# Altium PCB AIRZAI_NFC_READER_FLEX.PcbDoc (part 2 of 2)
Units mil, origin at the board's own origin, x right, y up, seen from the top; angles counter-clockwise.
Board outline 2897.24 x 5925.59 mil, 2 copper layers (Top Layer, Bottom Layer); 45 components, 43 nets, 193 pads, 92 vias.
Unrouted connection lines stored in the file: 129.

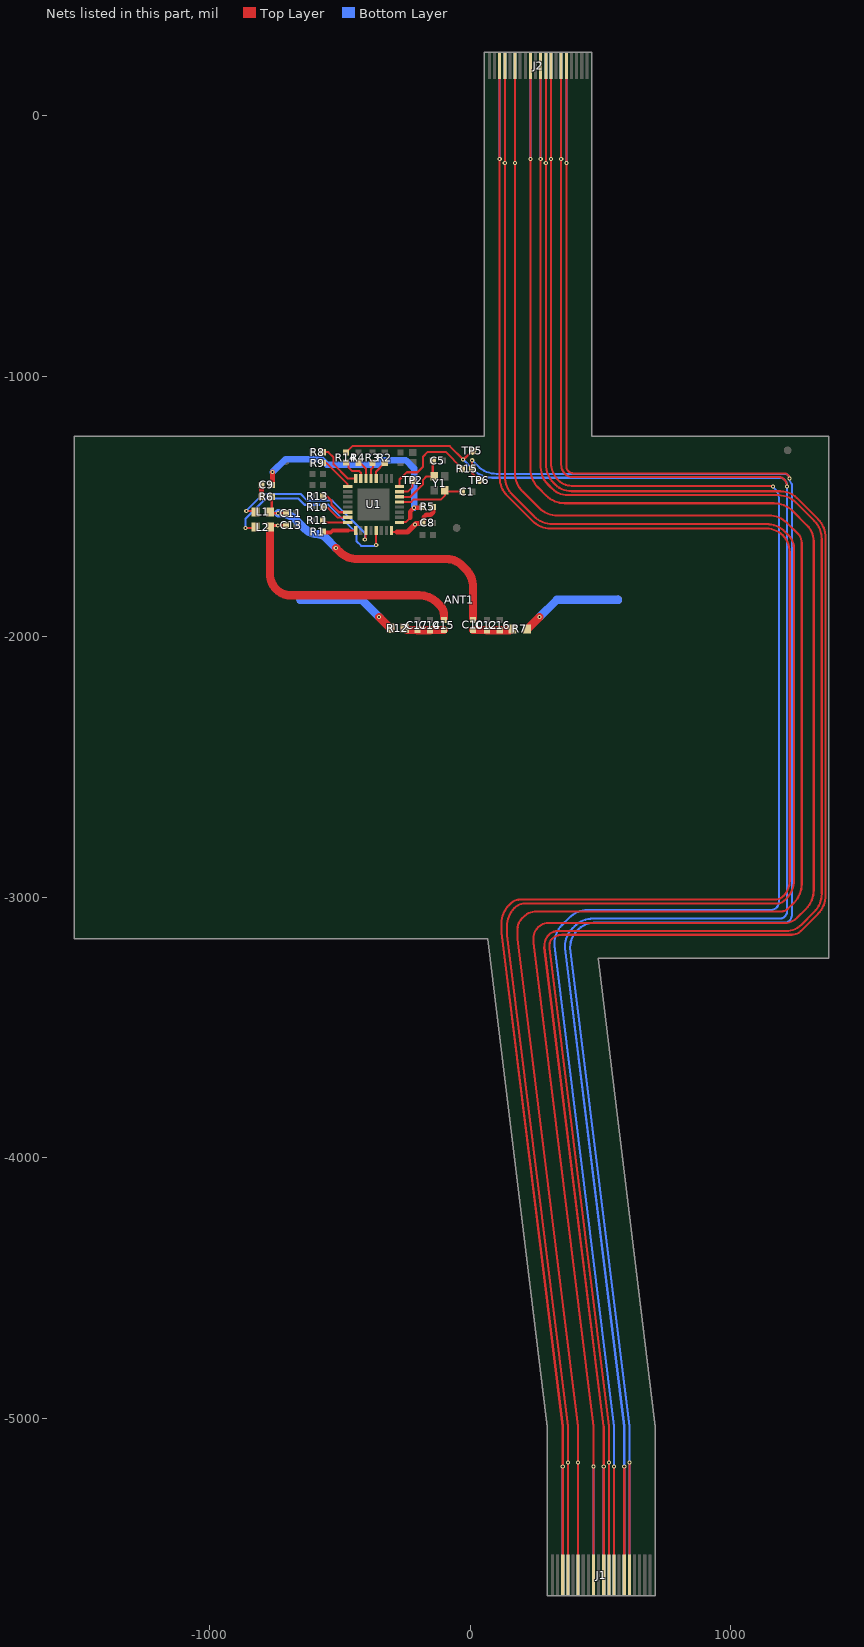
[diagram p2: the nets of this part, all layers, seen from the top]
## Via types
v1: diameter 16, hole 8, Top Layer to Bottom Layer, tented both sides, 81 vias
v2: diameter 19.68, hole 8, Top Layer to Bottom Layer, 9 vias
v3: diameter 30, hole 15, Top Layer to Bottom Layer, tented both sides, 2 vias

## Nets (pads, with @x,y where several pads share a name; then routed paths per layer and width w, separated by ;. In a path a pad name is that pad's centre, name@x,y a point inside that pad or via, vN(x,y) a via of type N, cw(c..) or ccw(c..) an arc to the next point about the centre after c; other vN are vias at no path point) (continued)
"LED Str DATA": J1.11 J2.11 | length 8505.9
  Top Layer w8: J2.11@270.72,192.91 270.72,-1348.01 ccw(c365.7,-1348.01) 298.54,-1415.17 308.25,-1424.88 ccw(c378.96,-1354.17) 315.47,-1431.43 ccw(c375.25,-1371.65) 375.25,-1456.19 1183.52,-1456.19 cw(c1183.52,-1549.31) 1249.37,-1483.46 1320.71,-1554.81 cw(c1250,-1625.52) 1350,-1625.52 1350,-2985.57 cw(c1250,-2985.57) 1320.71,-3056.28 1272,-3104.99 cw(c1211.64,-3044.64) 1211.64,-3129.99 335.8,-3129.99 ccw(c335.8,-3177.79) 302,-3143.99 ccw(c344.18,-3186.17) 284.53,-3186.17 284.53,-3190.73 ; 284.3,-3190.96 512.65,-5032.35 v1@512.65,-5186.17 ; J1.11@512.85,-5602.76 v1(512.85,-5186.17)
  Bottom Layer w8: v1@270.72,-164.99 J2.11@270.72,192.91 ; J1.11@512.85,-5602.76 v1(512.85,-5186.17)
  other v1: 270.72,-165.27
NetANT1_1: ANT1.1 R7.1 | length 396.1
  Top Layer w31.5: R7.1@217.78,-1969.52 ccw(c217.78,-1962.59) 222.68,-1967.49 v1(265.88,-1924.29)
  Bottom Layer w31.5: v1(265.88,-1924.29) 332.3,-1857.87 ; 332.3,-1857.85 ANT1.1@567.9,-1857.85
NetANT1_2: ANT1.2 R12.1 | length 391
  Top Layer w31.5: v1@-349.45,-1924.19 R12.1@-306.34,-1967.3
  Bottom Layer w31.5: ANT1.2@-652.1,-1857.85 -482.13,-1857.85 ; -482.13,-1857.87 -415.97,-1857.87 v1(-349.55,-1924.29)
NetC1_2: C1.2 U1.21 Y1.3 | length 268.4
  Top Layer w8: U1.21@-271.21,-1482.04 -225.83,-1482.04 -216.13,-1472.34 -111.34,-1472.34 -97.09,-1458.1 Y1.3@-97.09,-1437.14 -91.98,-1442.25 C1.2@-35.8,-1442.25
NetC5_2: C5.2 U1.22 Y1.1 | length 236.2
  Top Layer w8: U1.22@-271.21,-1462.36 -229.11,-1462.36 -181.8,-1415.05 -181.8,-1398.13 -167.8,-1384.13 -138.6,-1384.13 Y1.1@-138.46,-1383.99 -143.8,-1378.66 C5.2@-143.8,-1325.13
NetC9_1: C9.1 R6.2 | length 46.1
  Top Layer w20: R6.2@-801.38,-1462.43 -801.07,-1462.12 C9.1@-801.07,-1416.43
NetC9_2: C9.2 R5.2 U1.17 | length 919.8
  Top Layer w8: U1.17@-271.21,-1560.78 -269.11,-1558.68 -246.05,-1558.68 -230.8,-1543.43
  Top Layer w17: -230.8,-1543.43 -230.8,-1519.82 v1(-215.45,-1504.46) -186.26,-1504.46 R5.2@-182.95,-1501.15
  Top Layer w20: C9.2@-761.7,-1416.43 C9.2@-759.88,-1414.62 ; C9.2@-758.61,-1414.62 v1(-758.61,-1367.56)
  Bottom Layer w25: v1(-758.61,-1367.56) -708.66,-1317.6 -571.42,-1317.6 -550.14,-1338.88 -357.71,-1338.88 -341.17,-1322.35 -246.54,-1322.35 -215.45,-1353.44 v1(-215.45,-1504.46)
NetC10_1: C10.1 C12.2 C16.2 R7.2 | length 152.8
  Top Layer w31.5: C10.1@11.31,-1974.2 63.87,-1974.2 C12.2@64.22,-1974.55 C16.2@113.24,-1974.55 150.52,-1974.55 ccw(c150.52,-1957.38) R7.2@162.66,-1969.52
NetC10_2: C10.2 C11.2 L1.2 R6.1 | length 1115.1
  Top Layer w10: R6.1@-762.01,-1462.43 -762.01,-1513.62 L1.2@-768.82,-1520.43 -763.82,-1525.43 v1(-737.23,-1525.43) C11.2@-707.64,-1525.43 C11.2@-704.64,-1525.43
  Top Layer w31.5: v1@-515.38,-1658.99 -500.85,-1673.52 ccw(c-433.25,-1605.92) -433.25,-1701.52 -89.72,-1701.52 cw(c-89.72,-1783.46) -31.78,-1725.52 -17.98,-1739.32 cw(c-88.69,-1810.03) 11.31,-1810.03 11.31,-1896.52 C10.2@11.32,-1928.52
  Bottom Layer w31.5: v1(-737.23,-1525.43) -735.29,-1525.43 cw(c-735.29,-1625.43) -664.58,-1554.72 -632.16,-1587.13 ccw(c-587.78,-1542.75) -587.78,-1605.52 cw(c-587.78,-1651.22) -555.47,-1618.9 -516.31,-1658.06 -516.31,-1658.68 v1(-516,-1658.99)
NetC13_1: C13.1 C15.2 L2.2 | length 1011.1
  Top Layer w10: L2.2@-768.82,-1578.43 -762.82,-1572.43 v1(-738.6,-1572.43) C13.1@-707.63,-1572.43 C13.1@-704.63,-1572.43
  Top Layer w31.5: L2.2@-768.82,-1578.43 -768.82,-1758.02 ccw(c-683.32,-1758.02) -743.78,-1818.48 ccw(c-690.57,-1765.27) -690.57,-1840.52 -196.2,-1840.52 cw(c-196.2,-1940.52) -125.49,-1869.81 -115.78,-1879.52 cw(c-151.48,-1915.22) -100.99,-1915.22 C15.2@-100.99,-1927.52
NetC14_1: C14.1 C15.1 C17.1 R12.2 | length 152.3
  Top Layer w31.5: R12.2@-251.22,-1967.3 ccw(c-234.17,-1950.25) -234.17,-1974.36 C17.1@-202.78,-1974.36 -202.59,-1974.56 C14.1@-154.1,-1974.56 -153.9,-1974.36 C15.1@-100.99,-1974.36
NetL1_1: L1.1 U1.11 | length 646.1
  Top Layer w8: v1(-859.6,-1516.67) -827.7,-1516.67 L1.1@-823.94,-1520.43 ; v1(-404.6,-1626.67) -402.21,-1626.67 -403.07,-1625.81 -403.07,-1622.97 -401.27,-1621.17 -401.27,-1592.41 U1.11@-400.31,-1591.45
  Bottom Layer w8: v1(-859.6,-1516.67) -793.93,-1451 -651.42,-1451 -625.42,-1476.99 -529,-1476.99 -404.6,-1601.39 v1(-404.6,-1626.67)
NetL2_1: L2.1 U1.13 | length 761
  Top Layer w8: v1(-862.6,-1582.67) -828.18,-1582.67 L2.1@-823.94,-1578.43 ; v1(-360.94,-1647.99) U1.13@-360.94,-1591.45
  Bottom Layer w8: v1(-862.6,-1582.67) -862.6,-1547.12 -784.48,-1469 -659.99,-1469 -636,-1492.99 -545,-1492.99 -437,-1600.99 -437,-1631.88 -418.21,-1650.67 -363.61,-1650.67 v1(-360.94,-1647.99)
NetR1_1: R1.1 U1.9 | length 124.2
  Top Layer w8: -469.26,-1592.28 -440.14,-1591.92 U1.9@-439.68,-1591.45
  Top Layer w15: R1.1@-560.46,-1599.84 -535.83,-1599.93 -527.9,-1592.06 -469.26,-1592.28
NetR2_2: R2.2 U1.28 | length 74.9
  Top Layer w8: U1.28@-360.94,-1392.32 -360.94,-1365.16 -327.47,-1331.7 R2.2@-327.8,-1331.37
NetR3_2: R3.2 U1.29 | length 64.2
  Top Layer w8: U1.29@-380.62,-1392.32 -380.62,-1356.08 -373.8,-1349.26 -373.8,-1332.37 R3.2@-374.8,-1331.37
NetR4_2: R4.2 U1.30 | length 70.2
  Top Layer w8: R4.2@-422.55,-1331.37 -400.31,-1353.61 U1.30@-400.31,-1392.32
NetR8_1: R8.1 U1.32 | length 193.9
  Top Layer w8: R8.1@-563.88,-1292.96 R8.1@-565.74,-1291.1 ; R8.1@-557.73,-1291.1 R8.1@-565.74,-1291.1 ; U1.32@-439.68,-1392.32 -469.54,-1392.32 -524.42,-1337.43 -524.42,-1311.29 -544.61,-1291.1 R8.1@-565.74,-1291.1
NetR9_1: R9.1 U1.1 | length 138
  Top Layer w8: R9.1@-565.74,-1332.88 -551.42,-1332.88 -470.35,-1413.96 U1.1@-470.35,-1422.99
NetR10_1: R10.1 U1.7 | length 110
  Top Layer w8: R10.1@-565.77,-1505.92 -545.39,-1505.92 -510.21,-1541.1 U1.7@-470.35,-1541.1
NetR11_1: R11.1 U1.8 | length 102.7
  Top Layer w8: R11.1@-565.58,-1561.92 R11.1@-560.28,-1556.62 ; R11.1@-565.58,-1560.78 U1.8@-470.35,-1560.78
NetR13_1: R13.1 U1.6 | length 129.2
  Top Layer w8: R13.1@-565.58,-1461.92 -547.78,-1461.92 -533.26,-1476.43 -533.26,-1492.04 -503.74,-1521.57 -470.5,-1521.57 U1.6@-470.35,-1521.41
NetR14_1: R14.1 U1.31 | length 97.5
  Top Layer w8: R14.1@-469.22,-1331.25 -467.8,-1332.68 -467.8,-1348.82 -452.74,-1363.88 -425.42,-1363.88 -419.99,-1369.32 U1.31@-419.99,-1392.32
NetR15_1: R15.1 U1.24 | length 361.1
  Top Layer w8: U1.24@-271.21,-1422.99 -271.21,-1396.16 -243.05,-1367.99 -202.26,-1367.99 -181,-1346.73 -181,-1307.99 -163.01,-1290 -93.99,-1290 -31.69,-1352.31 R15.1@-31.69,-1354.57
NetTP2_1: TP2.1 U1.23 | length 94.4
  Top Layer w8: U1.23@-271.21,-1442.67 -240.01,-1442.67 -220.8,-1423.46 TP2.1@-220.8,-1387.43
NFC_INT: J1.12 J2.12 | length 8529.3
  Top Layer w8: J2.12@290.41,192.91 290.41,-1337.62 ccw(c390.41,-1337.62) 319.7,-1408.33 326.54,-1415.17 ccw(c388.89,-1352.82) 388.89,-1441 1192.24,-1441 cw(c1192.24,-1527.56) 1253.45,-1466.35 1335.71,-1548.62 cw(c1265,-1619.33) 1365,-1619.33 1365,-2992.57 cw(c1265,-2992.57) 1335.71,-3063.28 1269,-3129.99 cw(c1235.2,-3096.19) 1235.2,-3143.99 352.63,-3143.99 ccw(c352.63,-3198.62) 314,-3159.99 ccw(c335.73,-3181.72) 305,-3181.72 305,-3194.99 ; 304.69,-3195.03 532.54,-5032.35 v1(532.54,-5170.17) J1.12@532.54,-5602.76
  Bottom Layer w8: v1(290.41,-181.27) J2.12@290.41,192.91 ; J1.12@532.54,-5602.76 v1(532.54,-5170.17)
PWM1: J1.4 J2.4 | length 8627.8
  Top Layer w8: J2.4@132.93,192.91 132.93,-1384.14 ccw(c232.93,-1384.14) 162.22,-1454.85 245.25,-1537.88 ccw(c315.96,-1467.17) 315.96,-1567.17 1137.76,-1567.17 cw(c1137.76,-1667.17) 1208.47,-1596.46 1223,-1610.99 cw(c1174.72,-1659.28) 1243,-1659.28 1243,-2934.57 cw(c1143,-2934.57) 1213.71,-3005.28 1206,-3012.99 cw(c1179.44,-2986.44) 1179.44,-3023.99 211.04,-3023.99 ccw(c211.04,-3082.03) 170,-3040.99 169.94,-3041.05 ccw(c240.65,-3111.76) 140.65,-3111.76 140.65,-3142.16 ; 140.65,-3144.8 140.65,-3142.16 ; J1.4@375.06,-5602.76 v1(375.06,-5170.17) 375.06,-5032.35 140.97,-3144.76 140.65,-3142.16
  Bottom Layer w8: v1(132.93,-181.27) J2.4@132.93,192.91 ; J1.4@375.06,-5602.76 v1(375.06,-5170.17)
PWM2: J1.3 J2.3 | length 8603.9
  Top Layer w8: J2.3@113.24,192.91 113.24,-1388.15 ccw(c213.24,-1388.15) 142.53,-1458.86 238.56,-1554.88 ccw(c309.27,-1484.17) 309.27,-1584.17 1137.67,-1584.17 cw(c1137.67,-1672.32) 1200,-1609.99 cw(c1134.82,-1675.18) 1227,-1675.18 1227,-2937.05 cw(c1145.06,-2937.05) 1203,-2994.99 cw(c1169.2,-2961.19) 1169.2,-3008.99 191.21,-3008.99 ccw(c191.21,-3060.21) 155.01,-3023.98 149.39,-3029.6 ccw(c220.1,-3100.31) 120.1,-3100.31 120.1,-3135.23 355.37,-5032.35 v1(355.37,-5186.17) J1.3@355.37,-5602.76
  Bottom Layer w8: v1@113.24,-164.99 J2.3@113.24,192.91 ; J1.3@355.37,-5602.76 v1(355.37,-5186.17)
  other v1: 113.24,-165.27
SCL: J1.15 J2.15 R14.2 TP5.1 | length 10030.3
  Top Layer w8: R14.2@-476.42,-1291.93 -452.44,-1267.95 -78.23,-1267.95 v1(-27,-1319.18) -25.51,-1319.18 7.36,-1286.31 TP5.1@8.85,-1286.31 ; 349.42,-341.22 349.42,-1338.66 ccw(c401.06,-1338.66) 364.54,-1375.17 ccw(c391.1,-1348.62) 391.1,-1386.17 1185.31,-1386.17 cw(c1181.88,-1420.12) 1206,-1395.99 cw(c1179.44,-1422.55) v1(1217,-1422.55) ; 349.46,-341.22 J2.15@349.46,192.91 ; J1.15@591.59,-5602.76 591.59,-5203.22 591.54,-5203.17 v1(591.54,-5186.22) v1@591.59,-5186.17
  Bottom Layer w8: v1(-27,-1319.18) 13.7,-1359.88 ccw(c84.41,-1289.17) 84.41,-1389.17 1186,-1389.17 cw(c1186,-1420.17) 1217,-1420.17 v1(1217,-1422.55) 1217,-3052.61 cw(c1186.62,-3052.61) 1208.1,-3074.09 cw(c1189.03,-3055.02) 1189.03,-3081.99 479.17,-3081.99 479.08,-3081.9 471.51,-3081.9 ccw(c471.51,-3181.9) 400.8,-3111.19 392,-3119.99 ccw(c460.24,-3188.23) 363.74,-3188.23 363.74,-3194.99 591.59,-5032.35 ; v1(349.42,-165.22) J2.15@349.46,192.91 ; 591.54,-5032.35 591.54,-5203.17 591.59,-5203.22 J1.15@591.59,-5602.76
SDA: J1.16 J2.16 R15.2 TP6.1 | length 9603.2
  Top Layer w8: v1(7.69,-1322.35) 7.69,-1349.99 8,-1350.31 8,-1372.17 TP6.1@35,-1399.17 ; J2.16@369.15,192.91 369.15,-1343.91 ccw(c397.81,-1343.91) 377.54,-1364.17 ccw(c396.86,-1344.86) 396.86,-1372.17 1205.74,-1372.17 cw(c1205.74,-1392.07) 1219.8,-1378 1220.91,-1379.11 cw(c1208.02,-1391.99) v1(1226.25,-1391.99) ; J1.16@611.28,-5602.76 v1(611.28,-5170.17) 611.28,-5186.17
  Bottom Layer w8: v1(7.69,-1322.35) 30.22,-1344.88 ccw(c100.93,-1274.17) 100.93,-1374.17 1208.43,-1374.17 cw(c1208.43,-1391.99) v1(1226.25,-1391.99) 1226.25,-1393.71 ccw(c1252.72,-1393.71) 1234,-1412.43 cw(c1229.17,-1417.26) 1236,-1417.26 1236,-3064.44 cw(c1198.44,-3064.44) 1225,-3090.99 cw(c1208.1,-3074.09) 1208.1,-3097.99 473.53,-3097.99 ccw(c473.53,-3176.52) 418,-3120.99 410.28,-3128.71 ccw(c474.2,-3192.62) 383.81,-3192.62 ; v1(369.15,-181.27) J2.16@369.15,192.91 ; 383.38,-3193.05 611.47,-5032.35 ; J1.16@611.28,-5602.76 611.28,-5032.35
SPR_GPO1: J1.9 J2.9 | length 8532.6
  Top Layer w8: J2.9@231.35,192.91 231.35,-1355.89 ccw(c331.35,-1355.89) 260.64,-1426.6 291.93,-1457.88 ccw(c362.64,-1387.17) 362.64,-1487.17 1166.76,-1487.17 cw(c1166.76,-1587.17) 1237.47,-1516.46 1294.25,-1573.24 cw(c1234.5,-1632.99) 1319,-1632.99 1319,-2973.57 cw(c1219,-2973.57) 1289.71,-3044.28 1255,-3078.99 cw(c1206.72,-3030.71) 1206.72,-3098.99 299.63,-3098.99 ccw(c299.63,-3153.62) 261,-3114.99 ccw(c304.87,-3158.87) 242.83,-3158.87 242.83,-3174.01 473.28,-5032.35 v1@473.28,-5186.17 ; J1.9@473.48,-5602.76 v1(473.48,-5186.17)
  Bottom Layer w8: v1@231.35,-164.99 J2.9@231.35,192.91 ; J1.9@473.48,-5602.76 v1(473.48,-5186.17)
  other v1: 231.35,-165.27
SPR_GPO2: J1.6 J2.6 | length 8599
  Top Layer w8: J2.6@172.3,192.91 172.3,-1371.51 ccw(c272.3,-1371.51) 201.59,-1442.22 264.25,-1504.88 ccw(c334.96,-1434.17) 334.96,-1534.17 1146.98,-1534.17 cw(c1146.98,-1634.17) 1217.69,-1563.46 1259.22,-1604.99 cw(c1225.95,-1638.26) 1273,-1638.26 1273,-2949.57 cw(c1173,-2949.57) 1243.71,-3020.28 1220,-3043.99 cw(c1195.86,-3019.85) 1195.86,-3053.99 255.7,-3053.99 ccw(c255.7,-3125.69) 205,-3074.99 198.97,-3081.02 ccw(c239.94,-3121.99) 182,-3121.99 182,-3159.52 182.2,-3159.72 414.43,-5032.35 v1(414.43,-5170.17) J1.6@414.43,-5602.76
  Bottom Layer w8: v1(172.3,-181.27) J2.6@172.3,192.91 ; J1.6@414.43,-5602.76 v1(414.43,-5170.17)
TOFINT: J1.13 J2.13 | length 8189.4
  Top Layer w8: J2.13@310.09,192.91 310.09,-1330.49 ccw(c407.22,-1330.49) 338.54,-1399.17 ccw(c389.24,-1348.47) 389.24,-1420.17 v1@1159.48,-1420.17 ; J1.13@552.22,-5602.76 v1(552.22,-5186.17)
  Bottom Layer w8: v1@310.09,-164.99 J2.13@310.09,192.91 ; J1.13@552.22,-5602.76 552.22,-5032.35 323.12,-3184.94 323.12,-3177.29 cw(c423.12,-3177.29) 352.41,-3106.58 380.71,-3078.28 cw(c451.42,-3148.99) 451.42,-3048.99 1154.27,-3048.99 ccw(c1154.27,-3018.26) 1176,-3039.99 ccw(c1154.27,-3018.26) 1185,-3018.26 1185,-1465.99 ccw(c1139.13,-1465.99) 1171.56,-1433.56 v1@1162.71,-1424.7
  other v1: 1162.71,-1422.7 310.09,-165.27
VMID: C8.1 R5.1 U1.16 | length 227.7
  Top Layer w8: U1.16@-301.88,-1591.45 -301.88,-1595.02 -299.78,-1597.13 -279.8,-1597.13
  Top Layer w17: C8.1@-182.46,-1562.61 -179.15,-1559.3 -179.15,-1541.52 -169.19,-1531.56 -151.61,-1531.56 -141.61,-1521.56 -141.61,-1503.12 R5.1@-143.58,-1501.15
  Top Layer w20: -279.8,-1597.13 -240.65,-1597.13 v1(-212.26,-1568.74) -207.95,-1564.42 -184.28,-1564.42 C8.1@-182.46,-1562.61
pads on no net: U1.19 U1.20 U1.25 U1.26 U1.27
copper on no net:
  other v3: -107.1,-2889.35 22.9,-2771.24

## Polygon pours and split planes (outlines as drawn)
GND on Top Layer "gnd_top" (hatched 45Degree grid 30 track 9.5, remove dead copper, pour order 1): -1519.83,-3158.65 -1519.83,-1229.53 54.19,-1229.53 54.19,244.09 467.57,244.09 467.57,-1229.53 1377.42,-1229.53 1377.42,-3233.99 490.88,-3233.99 490.88,-3234.01 709.7,-5033.99 709.7,-5681.5 296.31,-5681.5 296.31,-5033.99 68.33,-3158.64 68.32,-3158.65
no net on Top Layer "3.3V Input Top" (solid, pour order 0): -1601.32,-1280.2

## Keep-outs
Keep-Out Layer:
  the board outline again, w0.5

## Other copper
Top Layer:
  rectangle net +5: 406.54,-1298.99 1271,-1249.99
  rectangle net +5: 406.54,-1298.99 458.42,-479.17
  rectangle net 3V3: 403.42,-405.99 425.42,71
  rectangle net +5: 433.42,-1298.99 458.42,80
  region net GND: 308.54,-5041.98 338.05,-5038.35 99.07,-3091.97 69.56,-3095.59
  rectangle net +5: 675.54,-5504.17 700.54,-5157.99
  rectangle net 3V3: 645.54,-5502.17 667.54,-5157.99
  pour cut-out: -471.17,-1391.49 -471.17,-1592.28 -270.38,-1592.28 -270.39,-1592.28 -270.39,-1391.49
  pour cut-out: -690,-1492.88 -767,-1492.88 -767,-1698.99 -404,-1698.99 -404,-1583.99 -599.51,-1583.99 -633,-1550.5 -633,-1492.88 -689.38,-1492.88 -690,-1493.5
  region net SPR_GPO1: 261,-3114.99
  pour cut-out: 54.19,244.09 467.57,244.09 467.57,133.42 54.19,133.42
  pour cut-out: 1169,-1693.99 -1253.21,-1693.99 -1253.21,-2935.09 1169,-2935.09
  pour cut-out: 296.31,-5514.17 709.7,-5514.17 709.7,-5681.5 296.31,-5681.5
Bottom Layer:
  rectangle net GND: -431,-1548 -313,-1430
  rectangle net +5: 406.54,-1298.99 1269,-1242.99
  rectangle net 3V3: 403,-378.17 425.42,74
  rectangle net 3V3: 324.54,-466.17 425.54,-331.99
  rectangle net 3V3: 404.54,-466.17 425.54,-350.17
  rectangle net 3V3: 262,-1360.88 386.54,-331.99
  rectangle net +5: 406.54,-1298.99 458.42,-479.17
  rectangle net +5: 433.42,-1298.99 458.42,94
  region net 3V3: 645.75,-5037.85 667.54,-5035.18 441.75,-3196.25 419.96,-3198.93
  region net +5: 676.54,-5032.35 700.81,-5029.37 479.08,-3223.51 454.81,-3226.49
  rectangle net +5: 675.54,-5504.17 700.54,-5025.17
  rectangle net 3V3: 645.54,-5502.17 667.54,-5033.99
  pour cut-out: 54.19,244.09 467.57,244.09 467.57,133.42 54.19,133.42
  pour cut-out: -1253.21,-2935.09 1169,-2935.09 1169,-1693.99 -1253.21,-1693.99
  pour cut-out: -1353.87,-3038.54
  pour cut-out: 296.31,-5681.5 296.31,-5514.17 709.7,-5514.17 709.7,-5681.5

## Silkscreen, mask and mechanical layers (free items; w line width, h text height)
Bottom Overlay:
  circle w12: c74,122 r4
  circle w20: c-51.69,-2325.5 r10.82
  circle w12: c315.51,-5502.17 r4
  lines w20: -248.48,-2040.88 ccw(c-51.69,-2325.5) -234.11,-2619.52 ; -220.49,-2088.64 ccw(c-51.69,-2325.5) -208.28,-2570.59 ; -194.5,-2138.59 ccw(c-51.69,-2325.5) -181.72,-2521.52 ; -160.7,-2186.28 ccw(c-51.69,-2325.5) -154.1,-2469.64 ; -132.84,-2228.13 ccw(c-51.69,-2325.5) -127.55,-2427.04 ; -100,-2384.23 cw(c-51.69,-2325.5) -99.68,-2266.5 ; -3.69,-2266.5 cw(c-51.69,-2325.5) -3.37,-2384.23 ; 24.18,-2427.04 ccw(c-51.69,-2325.5) 29.47,-2228.13 ; 50.73,-2469.64 ccw(c-51.69,-2325.5) 57.33,-2186.28 ; 78.35,-2521.52 ccw(c-51.69,-2325.5) 91.13,-2138.59 ; 104.91,-2570.59 ccw(c-51.69,-2325.5) 117.12,-2088.64 ; 130.74,-2619.52 ccw(c-51.69,-2325.5) 145.1,-2040.88
  text "J2" at 67,68 h28
  text "J1" at 355.37,-5486.48 h28
Mechanical 1:
  drawing of 4135 lines, arcs and shapes, not listed
  text "R0,4" at -4617.14,140.66 h137.8 r322.13
  text "R0,4" at -4387.64,115.26 h137.8 r28.27
  text "Bend End" at -198.69,87.35 h19.68
  text "9,35" at 5140.3,40.52 h137.8
  text "Bend Start" at -199.69,-13.65 h19.68
  text "R0,4" at -4847.75,-44.71 h137.8 r49.62
  text "R0,4" at -4137.05,-609.16 h137.8 r346.55
  text "1,9" at 6425.8,-647.94 h137.8 r90
  text "Bend End" at -199.69,-694.65 h19.68
  text "Bend Start" at -200.69,-795.65 h19.68
  text "18,3" at 7034.82,-807.61 h137.8 r90
  text "R1,5" at -4222.58,-905.85 h137.8 r297.71
  text "Top Ben End" at -208.83,-957.53 h19.68
  text "Top Ben Start" at -236.83,-1050.53 h19.68
  text "5,7" at 5183.26,-1353.32 h137.8
  text "10,6" at 845.61,-1573.16 h137.8
  text "42,2" at 7033.95,-1998.5 h137.8 r90
  text "R1,5" at -4465.85,-2072.61 h137.8 r52.37
  text "R1,7" at -4370.38,-2259.42 h137.8 r19.46
  text "3,2" at 5557.46,-2454.12 h137.8
  text "Old Bend Start" at -1047.78,-2676.52 h19.68
  text "Back Metal Plate Start" at -1203.78,-2934.52 h19.68
  text "Spring Start" at -1206.78,-3168.52 h19.68
  text "56" at 7026.2,-3931.56 h137.8 r90
  text "~}" at -354.14,-4459.45 h137.8
  text "R1,7" at -4247.43,-4462.57 h137.8 r337.84
  text "R1,7" at -4466.78,-4469.69 h137.8 r324.73
  text "R0,4" at -4386.72,-4734.22 h137.8 r323.84
  text "3,2" at 5319.6,-5011.59 h137.8
  text "Bottom Ben End" at -22,-5335 h19.68
  text "Bottom Ben Start" at -47,-5432 h19.68
  text "2" at 5405.36,-5584.93 h137.8
  text "6" at 7024.12,-5590.32 h137.8 r90
Mechanical 2:
  rectangle: 1109,-1452.99 1377.57,-1229.99
  rectangle: -156.52,-2935.09 72,-2726.09
  rectangle: -376,-1974.99 289,-1863.99
  region: 107,-1229.53 -872,-1229.53 -872,-1678.99 107,-1678.99
  rectangle: 54.19,-239.99 467.57,-95.99
  rectangle: 295.09,-5243.99 710,-5123.99
  rectangle: 54.19,118 467.57,244.09
  rectangle: 296.31,-5681.5 709.7,-5504.98
  lines w8: -1853.69,-2691.5 -1453.69,-2691.5 ; -1503.69,-2691.5 -1423.69,-2691.5 cw(c-1423.69,-2812.21) -1338.33,-2726.85 460.96,-4526.14 cw(c375.6,-4611.5) 496.31,-4611.5 496.31,-5111.99 ; -613.69,-1710.99 -597,-1688.99 ; -579.69,-1710.99 -597,-1688.99 ; -413,-1902.13 -391,-1884.81 ; -413,-1868.13 -391,-1884.81 ; -188,-2843.31 -166,-2825.99 ; -188,-2809.31 -166,-2825.99 ; -69,-165.99 44,-165.99 ; 22,-183.31 44,-165.99 ; 22,-149.31 44,-165.99 ; 23,89.69 45,107.01 ; 23,123.69 45,107.01 ; 179,-1762.99 179,-577.99 -69,-329.99 -69,59.01 -21,107.01 45,107.01 ; 352.69,-5473.99 370,-5495.99 ; 386.69,-5473.99 370,-5495.99 ; 479,-5089.99 496.31,-5111.99 ; 496.31,-4870.99 496.31,-4882.68 496.31,-4885.68 259,-5122.99 259,-5268.99 370,-5379.99 370,-5495.99 ; 513,-5089.99 496.31,-5111.99 ; 1226.31,-1489.99 1243,-1467.99 ; 1260.31,-1489.99 1243,-1467.99 ; -1453.69,-2691.5 ccw(c-1453.69,-2570.79) -1368.33,-2656.14 -597,-1884.81 ; -1453.69,-2691.5 -530.5,-2691.5 -396,-2825.99 -166,-2825.99 ; -597,-1884.81 -596.82,-1884.81 -475,-1762.99 1067,-1762.99 1243,-1586.99 1243,-1467.99 ; -597,-1884.81 -391,-1884.81 ; -597,-1884.81 -597,-1688.99
  text "Stiffener Locations" at -2403.69,-2706.17 h30
Mechanical 4:
  the board outline again, w0.5
Mechanical 17:
  text "NFC Flex" at 4588.1,-8143.43 h157.48
  text "NFCFLX-061319-001" at 4599,-8424 h127.95
  text "1" at 6960.83,-8445.81 h59.06
  text "1" at 7149.8,-8445.81 h59.06
  text "NOTES: /  / 1. ALL ASSEMBLY MATERIALS TO BE RoHS COMPLIANT. /  / 2. MATERIAL: /           • FLEXIBLE METAL CLAD DIELECTRIC IAW                 /             IPC-4204/11 E1E2 O0/0 CU W7 T/T /           • STIFFENER IAW IPC-4203/1-E1E8M1 /  / 3. FINISH:  IMMERSION GOLD /  / ALL EXPOSED CONDUCTIVE PATTERN AREAS NOT COVERED WITH COVERLAY MATERIAL OR OTHER PLATING  / SHALL BE IMMERSION GOLD (0.000030-0.000090 mm) OVER ELECTROLESS NICKEL (0.001-0.006 mm). /  / 4. LEGEND SHALL BE WHITE, PERMANENT, ORGANIC, NON-CONDUCTIVE UV OR EPOXY TYPE INK APPLIED  / TO THE TOP SIDE OF THE BOARD. THERE SHALL BE NO LEGEND ON ANY SOLDERABLE COMPONENT LAND. /  / 5. ALL ASSEMBLY MATERIALS TO BE RoHS COMPLIANT. /  / 6. ANY LABELS OR COMPOSITION OF, APPLIED TO THE BOARD NEED TO BE APPROVIED BY AIRZAI /  / 7. MINIMUM TRACE WIDTHS: /           EXTERNAL: 0.203 mm  INTERNAL: N/A /  / 8. MINIMUM SPACE BETWEEN FEATURES: /          EXTERNAL: 0.15 mm  INTERNAL: N/A /  / 9. Overall Board Thickness: 0.1mm" at -6774,-8665 h78.74
Mechanical 18:
  lines w5: -7130.85,-6349.75 -6930.85,-6349.75 ; -7130.85,-3974.75 -6930.85,-3974.75 ; -7130.85,-1599.75 -6930.85,-1599.75 ; -4630.85,-8724.75 -4630.85,-8524.75 ; -4630.85,575.25 -4630.85,775.25 ; -2130.85,-8724.75 -2130.85,-8524.75 ; -2130.85,575.25 -2130.85,775.25 ; 369.15,-8724.75 369.15,-8524.75 ; 369.15,575.25 369.15,775.25 ; 2869.15,-8724.75 2869.15,-8524.75 ; 2869.15,575.25 2869.15,775.25 ; 3168.35,-8226.97 7668.35,-8226.97 ; 3168.35,-7985.23 4239.02,-7985.23 ; 3168.35,-7751.18 4239.02,-7751.18 ; 3168.35,-7540.35 4239.02,-7540.35 ; 3169.15,-8524.75 7669.15,-8524.75 ; 3794.14,-8527.95 3794.14,-7327.95 ; 4239.02,-8526.97 4239.02,-7326.97 ; 4239.02,-7860.04 7668.2,-7860.04 ; 4578.98,-7326.97 7668.35,-7326.97 ; 4668.35,-7326.97 3168.35,-7326.97 ; 5369.15,-8724.75 5369.15,-8524.75 ; 5369.15,575.25 5369.15,775.25 ; 7291.97,-8526.97 7291.97,-8226.97 ; 7669.15,-7324.75 7669.15,-8524.75 ; 7669.15,-6349.75 7869.15,-6349.75 ; 7669.15,-3974.75 7869.15,-3974.75 ; 7669.15,-1599.75 7869.15,-1599.75 ; 1768.35,-8526.97 1768.35,-7326.97 3168.35,-7326.97 ; 1768.35,-8526.97 3168.35,-8526.97 ; 1768.35,-8526.97 3168.35,-8526.97 ; 3168.35,-8526.97 3168.35,-7326.97 ; 3168.35,-8526.97 7668.35,-8526.97 ; 3168.35,-8526.97 7668.35,-8526.97 ; 7668.35,-8526.97 7668.35,-7326.97 ; 7668.35,-8526.97 7668.35,-7326.97 ; 7669.15,-8524.75 -6930.85,-8524.75 -6930.85,575.25 7669.15,575.25 7669.15,-8524.75 ; -7130.85,-8724.75 7869.15,-8724.75 7869.15,775.25 -7130.85,775.25 -7130.85,-8724.75
  text "1" at -5899.51,645.25 h70
  text "2" at -3403.85,645.25 h70
  text "3" at -914.51,645.25 h70
  text "4" at 1592.16,645.25 h70
  text "5" at 4091.15,645.25 h70
  text "6" at 6596.15,645.25 h70
  text "A" at -7055.85,-497.75 h70
  text "A" at 7744.15,-497.75 h70
  text "B" at -7055.85,-2877.75 h70
  text "B" at 7744.15,-2877.75 h70
  text "C" at -7055.85,-5252.75 h70
  text "C" at 7744.15,-5252.75 h70
  text "AIRZAI PROPRIETARY & CONFIDENTIAL" at 3324.27,-7216.09 h127.95
  text "DATE:" at 3824.65,-7389.17 h45
  text "ENGINEER:" at 3190.79,-7395.47 h45
  text "UNLESS OTHERWISE SPECIFIED" at 1867.96,-7456.1 h59.06
  text "06/13/19" at 3831.98,-7497.78 h59.06
  text "FD" at 3383.67,-7504.05 h78.74
  text "DIMENSIONS ARE IN MM" at 1990.01,-7582.08 h59.06
  text "PCB DESIGNER:" at 3186.86,-7603.86 h45
  text "DATE:" at 3812.84,-7605.71 h45
  text "D" at -7055.85,-7622.75 h70
  text "D" at 7744.15,-7622.75 h70
  text "AIRZAI" at 4529.98,-7660.97 h127.95
  text "TOLERANCES" at 2190.79,-7708.07 h59.06
  text "06/13/19" at 3831.98,-7712.35 h59.06
  text "DFM" at 3357.29,-7713.93 h78.74
  text "DATE:" at 3812.84,-7818.3 h45
  text "CHECK" at 3186.86,-7820.39 h45
  text "ANGULAR" at 2675.05,-7865.55 h59.06
  text "DECIMALS" at 1871.9,-7877.36 h59.06
  text "TITLE:" at 4290.8,-7923.77 h45
  text "FD" at 3423.04,-7937.12 h78.74
  text ".XX +/- .127MM" at 1824.65,-8034.84 h59.06
  text "+/-" at 2663.23,-8038.78 h59.06
  text "REL" at 3198.67,-8051.38 h45
  text "DATE:" at 3828.59,-8058.46 h45
  text "FD" at 3413.2,-8153.66 h78.74
  text ".XXX +/- .080MM" at 1812.84,-8196.26 h59.06
  text "REV:" at 7314.42,-8290.75 h45
  text "SCALE:" at 3834.1,-8291.53 h45
  text "DWG NO:" at 4285.28,-8299.41 h45
  text "SIZE" at 3198.67,-8302.56 h45
  text "B" at 3402.41,-8433.15 h120
  text "DO NOT SCALE DRAWING" at 1867.96,-8436.41 h70.87
  text "B" at 7398.09,-8452.31 h120
  text "1:1" at 3882.72,-8456.77 h120
  text "SHEET" at 6749.85,-8488.38 h45
  text "OF" at 7013.63,-8488.38 h45
  text "1" at -5899.51,-8654.75 h70
  text "2" at -3403.85,-8654.75 h70
  text "3" at -914.51,-8654.75 h70
  text "4" at 1592.16,-8654.75 h70
  text "5" at 4091.15,-8654.75 h70
  text "6" at 6596.15,-8654.75 h70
